VERSION 5.8 ;
BUSBITCHARS "[]" ;
DIVIDERCHAR "/" ;
UNITS
    DATABASE MICRONS 1000 ;
END UNITS

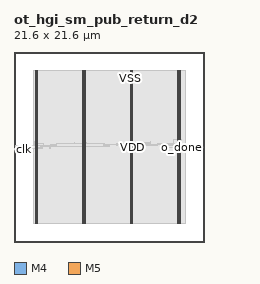
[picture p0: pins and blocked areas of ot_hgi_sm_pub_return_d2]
MACRO ot_hgi_sm_pub_return_d2
  FOREIGN ot_hgi_sm_pub_return_d2 0 0 ;
  CLASS BLOCK ;
  SIZE 21.6 BY 21.6 ;
  PIN clk
    DIRECTION INPUT ;
    USE SIGNAL ;
    PORT
      LAYER M4 ;
        RECT  0 10.512 0.084 10.536 ;
    END
  END clk
  PIN i_done
    DIRECTION INPUT ;
    USE SIGNAL ;
    PORT
      LAYER M4 ;
        RECT  0 10.608 0.084 10.632 ;
    END
  END i_done
  PIN i_fault
    DIRECTION INPUT ;
    USE SIGNAL ;
    PORT
      LAYER M4 ;
        RECT  0 10.704 0.084 10.728 ;
    END
  END i_fault
  PIN o_done
    DIRECTION OUTPUT ;
    USE SIGNAL ;
    PORT
      LAYER M4 ;
        RECT  21.516 10.704 21.6 10.728 ;
    END
  END o_done
  PIN o_fault
    DIRECTION OUTPUT ;
    USE SIGNAL ;
    PORT
      LAYER M4 ;
        RECT  21.516 10.8 21.6 10.824 ;
    END
  END o_fault
  PIN rn
    DIRECTION INPUT ;
    USE SIGNAL ;
    PORT
      LAYER M4 ;
        RECT  0 10.8 0.084 10.824 ;
    END
  END rn
  PIN VDD
    DIRECTION INOUT ;
    USE POWER ;
    PORT
      LAYER M5 ;
        RECT  18.792 2.151 18.912 19.449 ;
        RECT  13.392 2.151 13.512 19.449 ;
        RECT  7.992 2.151 8.112 19.449 ;
        RECT  2.592 2.151 2.712 19.449 ;
    END
  END VDD
  PIN VSS
    DIRECTION INOUT ;
    USE GROUND ;
    PORT
      LAYER M5 ;
        RECT  18.6 2.137 18.72 19.463 ;
        RECT  13.2 2.137 13.32 19.463 ;
        RECT  7.8 2.137 7.92 19.463 ;
        RECT  2.4 2.137 2.52 19.463 ;
    END
  END VSS
  # OT_OBS_CLOSED layer=M5 d_um=1.536 added=0
  OBS
    LAYER RVTN ;
     RECT  2.16 2.16 19.44 2.295 ;
     RECT  2.16 2.565 19.44 2.835 ;
     RECT  2.16 3.105 19.44 3.375 ;
     RECT  2.16 3.645 19.44 3.915 ;
     RECT  2.16 4.185 19.44 4.455 ;
     RECT  2.16 4.725 19.44 4.995 ;
     RECT  2.16 5.265 19.44 5.535 ;
     RECT  2.16 5.805 19.44 6.075 ;
     RECT  2.16 6.345 19.44 6.615 ;
     RECT  2.16 6.885 19.44 7.155 ;
     RECT  2.16 7.425 19.44 7.695 ;
     RECT  2.16 7.965 19.44 8.235 ;
     RECT  2.16 8.505 19.44 8.775 ;
     RECT  2.16 9.045 19.44 9.315 ;
     RECT  2.16 9.585 19.44 9.855 ;
     RECT  2.16 10.125 19.44 10.395 ;
     RECT  2.16 10.665 19.44 10.935 ;
     RECT  2.16 11.205 19.44 11.475 ;
     RECT  2.16 11.745 19.44 12.015 ;
     RECT  2.16 12.285 19.44 12.555 ;
     RECT  2.16 12.825 19.44 13.095 ;
     RECT  2.16 13.365 19.44 13.635 ;
     RECT  2.16 13.905 19.44 14.175 ;
     RECT  2.16 14.445 19.44 14.715 ;
     RECT  2.16 14.985 19.44 15.255 ;
     RECT  2.16 15.525 19.44 15.795 ;
     RECT  2.16 16.065 19.44 16.335 ;
     RECT  2.16 16.605 19.44 16.875 ;
     RECT  2.16 17.145 19.44 17.415 ;
     RECT  2.16 17.685 19.44 17.955 ;
     RECT  2.16 18.225 19.44 18.495 ;
     RECT  2.16 18.765 19.44 19.035 ;
     RECT  2.16 19.305 19.44 19.44 ;
    LAYER RVTP ;
     RECT  2.16 2.295 19.44 2.565 ;
     RECT  2.16 2.835 19.44 3.105 ;
     RECT  2.16 3.375 19.44 3.645 ;
     RECT  2.16 3.915 19.44 4.185 ;
     RECT  2.16 4.455 19.44 4.725 ;
     RECT  2.16 4.995 19.44 5.265 ;
     RECT  2.16 5.535 19.44 5.805 ;
     RECT  2.16 6.075 19.44 6.345 ;
     RECT  2.16 6.615 19.44 6.885 ;
     RECT  2.16 7.155 19.44 7.425 ;
     RECT  2.16 7.695 19.44 7.965 ;
     RECT  2.16 8.235 19.44 8.505 ;
     RECT  2.16 8.775 19.44 9.045 ;
     RECT  2.16 9.315 19.44 9.585 ;
     RECT  2.16 9.855 19.44 10.125 ;
     RECT  2.16 10.395 19.44 10.665 ;
     RECT  2.16 10.935 19.44 11.205 ;
     RECT  2.16 11.475 19.44 11.745 ;
     RECT  2.16 12.015 19.44 12.285 ;
     RECT  2.16 12.555 19.44 12.825 ;
     RECT  2.16 13.095 19.44 13.365 ;
     RECT  2.16 13.635 19.44 13.905 ;
     RECT  2.16 14.175 19.44 14.445 ;
     RECT  2.16 14.715 19.44 14.985 ;
     RECT  2.16 15.255 19.44 15.525 ;
     RECT  2.16 15.795 19.44 16.065 ;
     RECT  2.16 16.335 19.44 16.605 ;
     RECT  2.16 16.875 19.44 17.145 ;
     RECT  2.16 17.415 19.44 17.685 ;
     RECT  2.16 17.955 19.44 18.225 ;
     RECT  2.16 18.495 19.44 18.765 ;
     RECT  2.16 19.035 19.44 19.305 ;
    LAYER M1 ;
     RECT  2.16 2.151 19.44 19.449 ;
    LAYER M2 ;
     RECT  2.16 2.151 19.44 19.449 ;
     RECT  19.44 10.836 20.471 10.962 ;
     RECT  20.471 10.944 20.507 10.962 ;
    LAYER M3 ;
     RECT  2.415 2.143 2.505 2.413 ;
     RECT  7.815 2.143 7.905 2.413 ;
     RECT  13.215 2.143 13.305 2.413 ;
     RECT  18.615 2.143 18.705 2.413 ;
     RECT  18.615 2.413 18.897 10.435 ;
     RECT  2.415 2.413 2.697 10.597 ;
     RECT  4.068 10.597 4.086 10.633 ;
     RECT  2.34 10.597 2.697 10.669 ;
     RECT  18.504 10.435 18.897 10.741 ;
     RECT  2.34 10.669 3.222 10.795 ;
     RECT  20.484 10.699 20.502 10.795 ;
     RECT  4.068 10.633 4.194 10.831 ;
     RECT  7.815 2.413 8.097 10.831 ;
     RECT  20.448 10.795 20.502 10.859 ;
     RECT  10.8 10.867 10.818 10.891 ;
     RECT  4.068 10.831 4.806 10.895 ;
     RECT  2.304 10.795 3.222 10.939 ;
     RECT  4.176 10.895 4.806 10.939 ;
     RECT  17.568 10.741 18.897 10.939 ;
     RECT  10.152 10.891 10.818 10.967 ;
     RECT  20.484 10.859 20.502 10.967 ;
     RECT  4.176 10.939 5.418 10.975 ;
     RECT  7.488 10.831 8.097 10.975 ;
     RECT  16.272 10.939 16.29 10.975 ;
     RECT  17.424 10.939 18.897 10.975 ;
     RECT  13.215 2.413 13.497 10.987 ;
     RECT  14.868 10.939 14.886 10.987 ;
     RECT  10.152 10.967 10.242 11.003 ;
     RECT  2.304 10.939 3.33 11.011 ;
     RECT  7.38 10.975 8.097 11.011 ;
     RECT  14.832 10.987 14.886 11.011 ;
     RECT  16.164 10.975 16.29 11.011 ;
     RECT  12.96 10.987 13.497 11.035 ;
     RECT  14.436 11.011 16.29 11.035 ;
     RECT  17.424 10.975 18.99 11.035 ;
     RECT  7.38 11.011 8.154 11.101 ;
     RECT  11.7 10.939 11.718 11.101 ;
     RECT  12.672 11.035 13.497 11.101 ;
     RECT  4.176 10.975 5.706 11.129 ;
     RECT  14.436 11.035 18.99 11.129 ;
     RECT  2.304 11.011 3.402 11.165 ;
     RECT  4.86 11.129 4.878 11.165 ;
     RECT  5.688 11.129 5.706 11.165 ;
     RECT  6.84 11.101 8.154 11.165 ;
     RECT  10.224 11.003 10.242 11.165 ;
     RECT  11.7 11.101 13.497 11.165 ;
     RECT  14.436 11.129 15.498 11.165 ;
     RECT  16.272 11.129 18.99 11.165 ;
     RECT  7.815 11.165 8.154 11.173 ;
     RECT  11.7 11.165 12.006 11.201 ;
     RECT  16.272 11.165 16.29 11.201 ;
     RECT  17.424 11.165 17.442 11.201 ;
     RECT  6.84 11.165 6.858 11.273 ;
     RECT  7.815 11.173 8.226 11.273 ;
     RECT  14.832 11.165 15.498 11.309 ;
     RECT  15.48 11.309 15.498 11.399 ;
     RECT  2.304 11.165 2.697 11.435 ;
     RECT  11.988 11.201 12.006 11.435 ;
     RECT  18.18 11.165 18.99 11.669 ;
     RECT  18.18 11.669 18.897 11.705 ;
     RECT  2.415 11.435 2.697 19.187 ;
     RECT  7.815 11.273 8.097 19.187 ;
     RECT  13.215 11.165 13.497 19.187 ;
     RECT  18.615 11.705 18.897 19.187 ;
     RECT  2.415 19.187 2.505 19.457 ;
     RECT  7.815 19.187 7.905 19.457 ;
     RECT  13.215 19.187 13.305 19.457 ;
     RECT  18.615 19.187 18.705 19.457 ;
    LAYER M4 ;
     RECT  0.06 10.512 0.133 10.824 ;
     RECT  0.133 10.512 0.179 10.92 ;
     RECT  0.179 10.608 2.408 10.92 ;
     RECT  2.408 2.148 2.512 19.452 ;
     RECT  2.512 2.418 2.704 19.182 ;
     RECT  2.704 10.704 3.017 11.016 ;
     RECT  3.017 10.896 4.849 11.016 ;
     RECT  4.849 10.896 7.808 11.16 ;
     RECT  7.808 2.148 7.912 19.452 ;
     RECT  7.912 2.418 8.104 19.182 ;
     RECT  8.104 10.896 10.181 11.16 ;
     RECT  10.181 11.04 10.253 11.16 ;
     RECT  10.253 11.04 12.949 11.064 ;
     RECT  12.949 10.992 13.208 11.064 ;
     RECT  13.208 2.148 13.312 19.452 ;
     RECT  13.312 2.418 13.504 19.182 ;
     RECT  13.504 10.992 14.861 11.016 ;
     RECT  15.325 11.04 16.913 11.064 ;
     RECT  18.608 2.148 18.712 19.452 ;
     RECT  18.712 2.418 18.904 19.182 ;
     RECT  20.437 10.8 20.473 10.824 ;
     RECT  20.473 10.704 21.564 10.824 ;
    LAYER M5 ;
     RECT  2.4 2.137 2.52 2.151 ;
     RECT  7.8 2.137 7.92 2.151 ;
     RECT  13.2 2.137 13.32 2.151 ;
     RECT  18.6 2.137 18.72 2.151 ;
     RECT  0.144 10.501 0.168 10.931 ;
     RECT  2.4 2.151 2.712 19.449 ;
     RECT  7.8 2.151 8.112 19.449 ;
     RECT  13.2 2.151 13.512 19.449 ;
     RECT  18.6 2.151 18.912 19.449 ;
     RECT  2.4 19.449 2.52 19.463 ;
     RECT  7.8 19.449 7.92 19.463 ;
     RECT  13.2 19.449 13.32 19.463 ;
     RECT  18.6 19.449 18.72 19.463 ;
  END
END ot_hgi_sm_pub_return_d2
END LIBRARY
